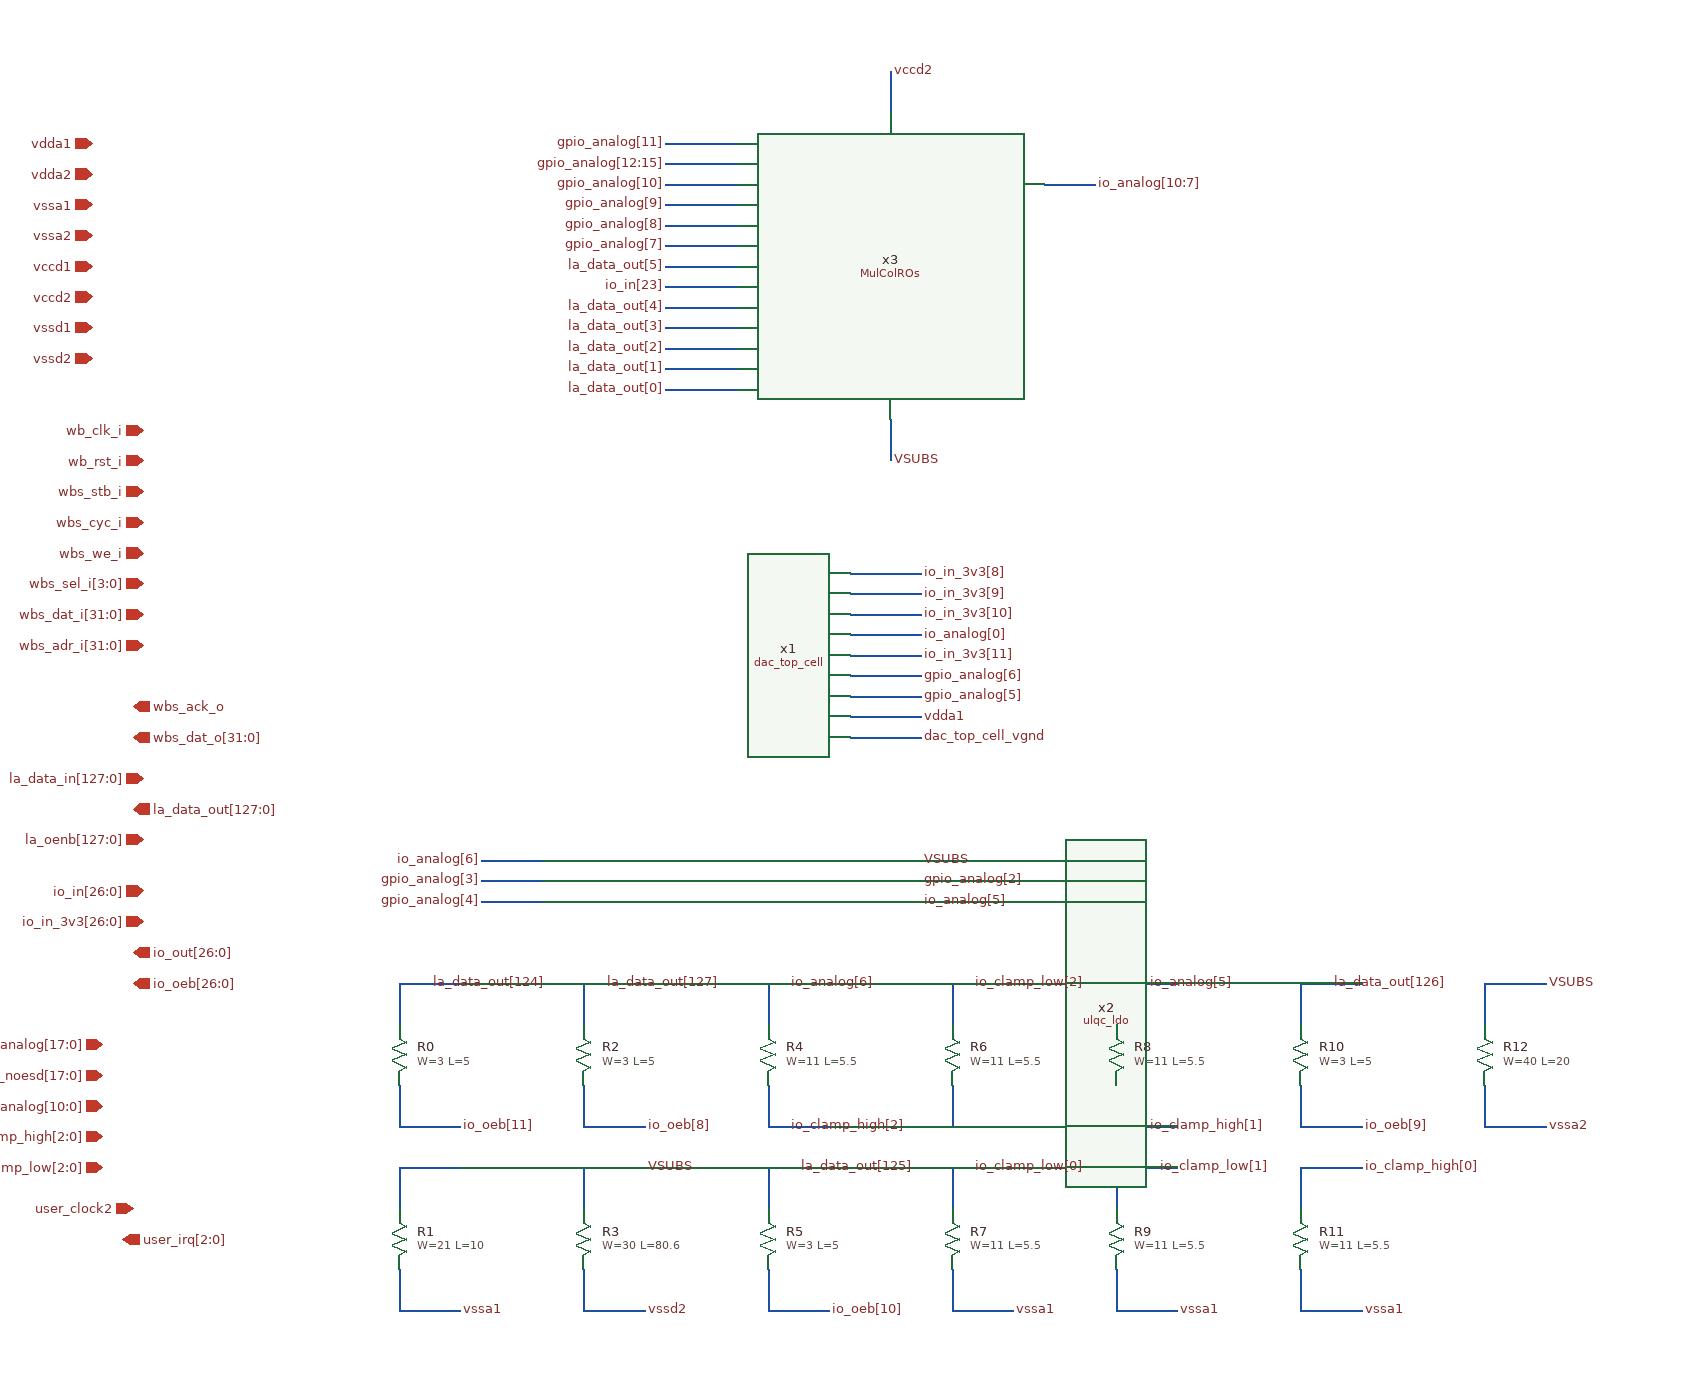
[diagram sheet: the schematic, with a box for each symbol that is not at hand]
v {xschem version=3.1.0 file_version=1.2
}
G {}
K {}
V {}
S {}
E {}
N 4440 -490 4440 -450 {
lab=VSUBS}
N 4440 -830 4440 -790 {
lab=vccd2}
N 4220 -760 4290 -760 {
lab=gpio_analog[11]}
N 4220 -740 4290 -740 {
lab=gpio_analog[12:15]}
N 4220 -720 4290 -720 {
lab=gpio_analog[10]}
N 4220 -700 4290 -700 {
lab=gpio_analog[9]}
N 4220 -680 4290 -680 {
lab=gpio_analog[8]}
N 4220 -660 4290 -660 {
lab=gpio_analog[7]}
N 4220 -640 4290 -640 {
lab=la_data_out[5]}
N 4220 -620 4290 -620 {
lab=io_in[23]}
N 4220 -600 4290 -600 {
lab=la_data_out[4]}
N 4220 -580 4290 -580 {
lab=la_data_out[3]}
N 4220 -560 4290 -560 {
lab=la_data_out[2]}
N 4220 -540 4290 -540 {
lab=la_data_out[1]}
N 4220 -520 4290 -520 {
lab=la_data_out[0]}
N 4590 -720 4640 -720 {
lab=io_analog[10:7]}
N 4400 -340 4470 -340 {
lab=io_in_3v3[8]}
N 4400 -320 4470 -320 {
lab=io_in_3v3[9]}
N 4400 -300 4470 -300 {
lab=io_in_3v3[10]}
N 4400 -280 4470 -280 {
lab=io_analog[0]}
N 4400 -260 4470 -260 {
lab=io_in_3v3[11]}
N 4400 -240 4470 -240 {
lab=gpio_analog[6]}
N 4400 -220 4470 -220 {
lab=gpio_analog[5]}
N 4400 -200 4470 -200 {
lab=vdda1}
N 4400 -180 4470 -180 {
lab=dac_top_cell_vgnd}
N 3960 60 3960 100 {
lab=la_data_out[124]}
N 3960 60 4020 60 {
lab=la_data_out[124]}
N 3960 160 3960 200 {
lab=io_oeb[11]}
N 3960 200 4020 200 {
lab=io_oeb[11]}
N 3960 240 3960 280 {
lab=#net1}
N 3960 240 4020 240 {
lab=#net1}
N 3960 340 3960 380 {
lab=vssa1}
N 3960 380 4020 380 {
lab=vssa1}
N 4140 60 4140 100 {
lab=la_data_out[127]}
N 4140 60 4200 60 {
lab=la_data_out[127]}
N 4140 160 4140 200 {
lab=io_oeb[8]}
N 4140 200 4200 200 {
lab=io_oeb[8]}
N 4140 240 4140 280 {
lab=VSUBS}
N 4140 240 4200 240 {
lab=VSUBS}
N 4140 340 4140 380 {
lab=vssd2}
N 4140 380 4200 380 {
lab=vssd2}
N 4320 60 4320 100 {
lab=io_analog[6]}
N 4320 60 4380 60 {
lab=io_analog[6]}
N 4320 160 4320 200 {
lab=io_clamp_high[2]}
N 4320 200 4380 200 {
lab=io_clamp_high[2]}
N 4320 240 4320 280 {
lab=la_data_out[125]}
N 4320 240 4380 240 {
lab=la_data_out[125]}
N 4320 340 4320 380 {
lab=io_oeb[10]}
N 4320 380 4380 380 {
lab=io_oeb[10]}
N 4500 60 4500 100 {
lab=io_clamp_low[2]}
N 4500 60 4560 60 {
lab=io_clamp_low[2]}
N 4500 160 4500 200 {
lab=#net2}
N 4500 200 4560 200 {
lab=#net2}
N 4500 240 4500 280 {
lab=io_clamp_low[0]}
N 4500 240 4560 240 {
lab=io_clamp_low[0]}
N 4500 340 4500 380 {
lab=vssa1}
N 4500 380 4560 380 {
lab=vssa1}
N 4660 60 4660 100 {
lab=io_analog[5]}
N 4660 60 4720 60 {
lab=io_analog[5]}
N 4660 160 4660 200 {
lab=io_clamp_high[1]}
N 4660 200 4720 200 {
lab=io_clamp_high[1]}
N 4660 240 4660 280 {
lab=io_clamp_low[1]}
N 4660 240 4720 240 {
lab=io_clamp_low[1]}
N 4660 340 4660 380 {
lab=vssa1}
N 4660 380 4720 380 {
lab=vssa1}
N 4840 60 4840 100 {
lab=la_data_out[126]}
N 4840 60 4900 60 {
lab=la_data_out[126]}
N 4840 160 4840 200 {
lab=io_oeb[9]}
N 4840 200 4900 200 {
lab=io_oeb[9]}
N 4840 240 4840 280 {
lab=io_clamp_high[0]}
N 4840 240 4900 240 {
lab=io_clamp_high[0]}
N 4840 340 4840 380 {
lab=vssa1}
N 4840 380 4900 380 {
lab=vssa1}
N 5020 60 5020 100 {
lab=VSUBS}
N 5020 60 5080 60 {
lab=VSUBS}
N 5020 160 5020 200 {
lab=vssa2}
N 5020 200 5080 200 {
lab=vssa2}
N 4040 -60 4100 -60 {
lab=io_analog[6]}
N 4040 -40 4100 -40 {
lab=gpio_analog[3]}
N 4040 -20 4100 -20 {
lab=gpio_analog[4]}
N 4400 -60 4470 -60 {
lab=VSUBS}
N 4400 -40 4470 -40 {
lab=gpio_analog[2]}
N 4400 -20 4470 -20 {
lab=#net3}
C {devices/iopin.sym} 3660 -760 0 0 {name=p1 lab=vdda1}
C {devices/iopin.sym} 3660 -730 0 0 {name=p2 lab=vdda2}
C {devices/iopin.sym} 3660 -700 0 0 {name=p3 lab=vssa1}
C {devices/iopin.sym} 3660 -670 0 0 {name=p4 lab=vssa2}
C {devices/iopin.sym} 3660 -640 0 0 {name=p5 lab=vccd1}
C {devices/iopin.sym} 3660 -610 0 0 {name=p6 lab=vccd2}
C {devices/iopin.sym} 3660 -580 0 0 {name=p7 lab=vssd1}
C {devices/iopin.sym} 3660 -550 0 0 {name=p8 lab=vssd2}
C {devices/ipin.sym} 3710 -480 0 0 {name=p9 lab=wb_clk_i}
C {devices/ipin.sym} 3710 -450 0 0 {name=p10 lab=wb_rst_i}
C {devices/ipin.sym} 3710 -420 0 0 {name=p11 lab=wbs_stb_i}
C {devices/ipin.sym} 3710 -390 0 0 {name=p12 lab=wbs_cyc_i}
C {devices/ipin.sym} 3710 -360 0 0 {name=p13 lab=wbs_we_i}
C {devices/ipin.sym} 3710 -330 0 0 {name=p14 lab=wbs_sel_i[3:0]}
C {devices/ipin.sym} 3710 -300 0 0 {name=p15 lab=wbs_dat_i[31:0]}
C {devices/ipin.sym} 3710 -270 0 0 {name=p16 lab=wbs_adr_i[31:0]}
C {devices/opin.sym} 3700 -210 0 0 {name=p17 lab=wbs_ack_o}
C {devices/opin.sym} 3700 -180 0 0 {name=p18 lab=wbs_dat_o[31:0]}
C {devices/ipin.sym} 3710 -140 0 0 {name=p19 lab=la_data_in[127:0]}
C {devices/opin.sym} 3700 -110 0 0 {name=p20 lab=la_data_out[127:0]}
C {devices/ipin.sym} 3710 -30 0 0 {name=p21 lab=io_in[26:0]}
C {devices/ipin.sym} 3710 0 0 0 {name=p22 lab=io_in_3v3[26:0]}
C {devices/ipin.sym} 3700 280 0 0 {name=p23 lab=user_clock2}
C {devices/opin.sym} 3700 30 0 0 {name=p24 lab=io_out[26:0]}
C {devices/opin.sym} 3700 60 0 0 {name=p25 lab=io_oeb[26:0]}
C {devices/iopin.sym} 3670 120 0 0 {name=p26 lab=gpio_analog[17:0]}
C {devices/iopin.sym} 3670 150 0 0 {name=p27 lab=gpio_noesd[17:0]}
C {devices/iopin.sym} 3670 180 0 0 {name=p29 lab=io_analog[10:0]}
C {devices/iopin.sym} 3670 210 0 0 {name=p30 lab=io_clamp_high[2:0]}
C {devices/iopin.sym} 3670 240 0 0 {name=p31 lab=io_clamp_low[2:0]}
C {devices/opin.sym} 3690 310 0 0 {name=p32 lab=user_irq[2:0]}
C {devices/ipin.sym} 3710 -80 0 0 {name=p28 lab=la_oenb[127:0]}
C {MulColROs.sym} 4440 -640 0 0 {name=x3}
C {devices/lab_pin.sym} 4200 380 0 1 {name=l33 sig_type=std_logic lab=vssd2}
C {devices/lab_pin.sym} 4440 -830 0 1 {name=l34 sig_type=std_logic lab=vccd2}
C {devices/lab_pin.sym} 4220 -620 0 0 {name=l35 sig_type=std_logic lab=io_in[23]}
C {devices/lab_pin.sym} 4220 -640 0 0 {name=l38 sig_type=std_logic lab=la_data_out[5]}
C {devices/lab_pin.sym} 4220 -600 0 0 {name=l36 sig_type=std_logic lab=la_data_out[4]}
C {devices/lab_pin.sym} 4220 -580 0 0 {name=l37 sig_type=std_logic lab=la_data_out[3]}
C {devices/lab_pin.sym} 4220 -540 0 0 {name=l39 sig_type=std_logic lab=la_data_out[1]}
C {devices/lab_pin.sym} 4220 -560 0 0 {name=l40 sig_type=std_logic lab=la_data_out[2]}
C {devices/lab_pin.sym} 4220 -520 0 0 {name=l41 sig_type=std_logic lab=la_data_out[0]}
C {devices/lab_pin.sym} 4220 -740 0 0 {name=l42 sig_type=std_logic lab=gpio_analog[12:15]}
C {devices/lab_pin.sym} 4220 -760 0 0 {name=l43 sig_type=std_logic lab=gpio_analog[11]}
C {devices/lab_pin.sym} 4220 -720 0 0 {name=l44 sig_type=std_logic lab=gpio_analog[10]}
C {devices/lab_pin.sym} 4220 -700 0 0 {name=l45 sig_type=std_logic lab=gpio_analog[9]}
C {devices/lab_pin.sym} 4220 -680 0 0 {name=l46 sig_type=std_logic lab=gpio_analog[8]}
C {devices/lab_pin.sym} 4220 -660 0 0 {name=l47 sig_type=std_logic lab=gpio_analog[7]}
C {devices/lab_pin.sym} 4640 -720 0 1 {name=l48 sig_type=std_logic lab=io_analog[10:7]}
C {top_cell_esd/tb/dac_top_cell.sym} 4250 -260 0 0 {name=x1}
C {devices/lab_pin.sym} 4470 -340 2 0 {name=l1 sig_type=std_logic lab=io_in_3v3[8]}
C {devices/lab_pin.sym} 4470 -320 2 0 {name=l2 sig_type=std_logic lab=io_in_3v3[9]}
C {devices/lab_pin.sym} 4470 -300 2 0 {name=l3 sig_type=std_logic lab=io_in_3v3[10]}
C {devices/lab_pin.sym} 4470 -260 2 0 {name=l4 sig_type=std_logic lab=io_in_3v3[11]}
C {devices/lab_pin.sym} 4470 -280 0 1 {name=l5 sig_type=std_logic lab=io_analog[0]}
C {devices/lab_pin.sym} 5080 200 0 1 {name=l6 sig_type=std_logic lab=vssa2}
C {devices/lab_pin.sym} 4470 -200 0 1 {name=l7 sig_type=std_logic lab=vdda1}
C {devices/lab_pin.sym} 4470 -240 2 0 {name=l8 sig_type=std_logic lab=gpio_analog[6]}
C {devices/lab_pin.sym} 4470 -220 2 0 {name=l9 sig_type=std_logic lab=gpio_analog[5]}
C {ulqc_ldo.sym} 4250 -40 0 0 {name=x2}
C {sky130_fd_pr/res_generic_m2.sym} 3960 130 0 0 {name=R0
W=3
L=5
model=res_generic_m2
mult=1}
C {sky130_fd_pr/res_generic_m4.sym} 3960 310 0 0 {name=R1
W=21
L=10
model=res_generic_m4
mult=1}
C {sky130_fd_pr/res_generic_m2.sym} 4140 130 0 0 {name=R2
W=3
L=5
model=res_generic_m2
mult=1}
C {sky130_fd_pr/res_generic_m4.sym} 4140 310 0 0 {name=R3
W=30
L=80.6
model=res_generic_m4
mult=1}
C {sky130_fd_pr/res_generic_m3.sym} 4320 130 0 0 {name=R4
W=11
L=5.5
model=res_generic_m3
mult=1}
C {sky130_fd_pr/res_generic_m2.sym} 4320 310 0 0 {name=R5
W=3
L=5
model=res_generic_m2
mult=1}
C {sky130_fd_pr/res_generic_m3.sym} 4500 130 0 0 {name=R6
W=11
L=5.5
model=res_generic_m3
mult=1}
C {sky130_fd_pr/res_generic_m3.sym} 4500 310 0 0 {name=R7
W=11
L=5.5
model=res_generic_m3
mult=1}
C {sky130_fd_pr/res_generic_m3.sym} 4660 130 0 0 {name=R8
W=11
L=5.5
model=res_generic_m3
mult=1}
C {sky130_fd_pr/res_generic_m3.sym} 4660 310 0 0 {name=R9
W=11
L=5.5
model=res_generic_m3
mult=1}
C {sky130_fd_pr/res_generic_m2.sym} 4840 130 0 0 {name=R10
W=3
L=5
model=res_generic_m2
mult=1}
C {sky130_fd_pr/res_generic_m3.sym} 4840 310 0 0 {name=R11
W=11
L=5.5
model=res_generic_m3
mult=1}
C {sky130_fd_pr/res_generic_m5.sym} 5020 130 0 0 {name=R12
W=40
L=20
model=res_generic_m5
mult=1}
C {devices/lab_pin.sym} 4200 240 0 1 {name=l10 sig_type=std_logic lab=VSUBS}
C {devices/lab_pin.sym} 5080 60 0 1 {name=l11 sig_type=std_logic lab=VSUBS}
C {devices/lab_pin.sym} 3990 60 2 0 {name=l12 sig_type=std_logic lab=la_data_out[124]}
C {devices/lab_pin.sym} 4350 240 2 0 {name=l13 sig_type=std_logic lab=la_data_out[125]}
C {devices/lab_pin.sym} 4870 60 2 0 {name=l14 sig_type=std_logic lab=la_data_out[126]}
C {devices/lab_pin.sym} 4160 60 2 0 {name=l15 sig_type=std_logic lab=la_data_out[127]}
C {devices/lab_pin.sym} 4470 -60 0 1 {name=l16 sig_type=std_logic lab=VSUBS}
C {devices/lab_pin.sym} 4440 -450 0 1 {name=l17 sig_type=std_logic lab=VSUBS}
C {devices/lab_pin.sym} 4020 200 2 0 {name=l18 sig_type=std_logic lab=io_oeb[11]}
C {devices/lab_pin.sym} 4200 200 2 0 {name=l19 sig_type=std_logic lab=io_oeb[8]}
C {devices/lab_pin.sym} 4900 200 2 0 {name=l20 sig_type=std_logic lab=io_oeb[9]}
C {devices/lab_pin.sym} 4380 380 2 0 {name=l21 sig_type=std_logic lab=io_oeb[10]}
C {devices/lab_pin.sym} 4470 -180 0 1 {name=l22 sig_type=std_logic lab=dac_top_cell_vgnd}
C {devices/lab_pin.sym} 4720 380 0 1 {name=l23 sig_type=std_logic lab=vssa1}
C {devices/lab_pin.sym} 4690 200 2 0 {name=l24 sig_type=std_logic lab=io_clamp_high[1]}
C {devices/lab_pin.sym} 4340 60 0 1 {name=l25 sig_type=std_logic lab=io_analog[6]}
C {devices/lab_pin.sym} 4690 60 0 1 {name=l26 sig_type=std_logic lab=io_analog[5]}
C {devices/lab_pin.sym} 4340 200 2 0 {name=l27 sig_type=std_logic lab=io_clamp_high[2]}
C {devices/lab_pin.sym} 4020 380 0 1 {name=l28 sig_type=std_logic lab=vssa1}
C {devices/lab_pin.sym} 4560 380 0 1 {name=l29 sig_type=std_logic lab=vssa1}
C {devices/lab_pin.sym} 4900 380 0 1 {name=l30 sig_type=std_logic lab=vssa1}
C {devices/lab_pin.sym} 4900 240 2 0 {name=l31 sig_type=std_logic lab=io_clamp_high[0]}
C {devices/lab_pin.sym} 4520 240 2 0 {name=l32 sig_type=std_logic lab=io_clamp_low[0]}
C {devices/lab_pin.sym} 4700 240 2 0 {name=l49 sig_type=std_logic lab=io_clamp_low[1]}
C {devices/lab_pin.sym} 4520 60 2 0 {name=l50 sig_type=std_logic lab=io_clamp_low[2]}
C {devices/lab_pin.sym} 4040 -60 2 1 {name=l51 sig_type=std_logic lab=io_analog[6]}
C {devices/lab_pin.sym} 4040 -40 0 0 {name=l52 sig_type=std_logic lab=gpio_analog[3]}
C {devices/lab_pin.sym} 4040 -20 0 0 {name=l53 sig_type=std_logic lab=gpio_analog[4]}
C {devices/lab_pin.sym} 4470 -40 2 0 {name=l54 sig_type=std_logic lab=gpio_analog[2]}
C {devices/lab_pin.sym} 4470 -20 0 1 {name=l55 sig_type=std_logic lab=io_analog[5]}
